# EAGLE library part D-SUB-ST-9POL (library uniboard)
D-SUB-Stecker, 9-polig, gewinkelt, RM 9,4

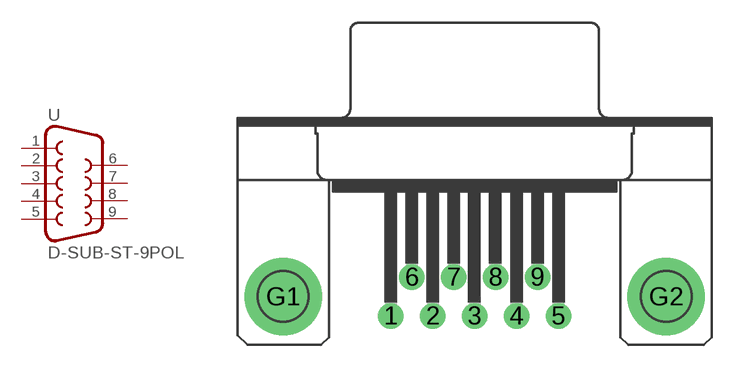
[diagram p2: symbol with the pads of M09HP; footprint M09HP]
Designator prefix -

## D-SUB-ST-9POL  [M09HP]
1  1  pas
2  2  pas
3  3  pas
4  4  pas
5  5  pas
6  6  pas
7  7  pas
8  8  pas
9  9  pas

## Footprint M09HP (pad centres in mm)
D-SUB-Stecker, 9-polig, gewinkelt
drill 1.016 pad 1.676 round: 1 -5.486,-1.27; 2 -2.743,-1.27; 3 0,-1.27; 4 2.743,-1.27; 5 5.486,-1.27; 6 -4.115,1.27; 7 -1.372,1.27; 8 1.372,1.27; 9 4.115,1.27
drill 3.302 pad 5.08 round: G1 -12.522,0; G2 12.522,0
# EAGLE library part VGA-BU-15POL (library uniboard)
VGA-Buchse 15pol

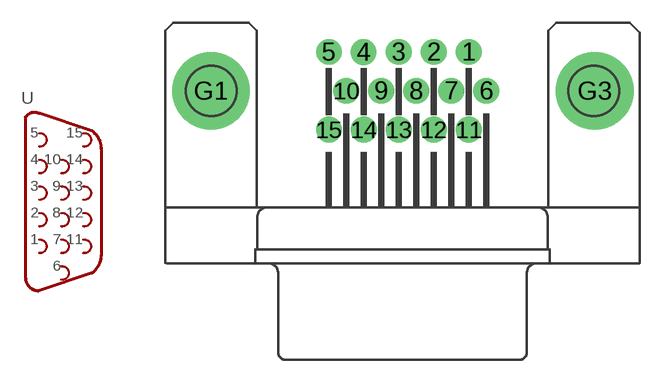
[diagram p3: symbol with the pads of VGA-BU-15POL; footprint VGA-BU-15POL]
Designator prefix -

## VGA-BU-15POL  [VGA-BU-15POL]
1  1  pas
2  2  pas
3  3  pas
4  4  pas
5  5  pas
6  6  pas
7  7  pas
8  8  pas
9  9  pas
10  10  pas
11  11  pas
12  12  pas
13  13  pas
14  14  pas
15  15  pas

## Footprint VGA-BU-15POL (pad centres in mm)
VGA-Buchse 15-polig
drill 1.016 pad 1.676 round: 1 4.329,2.54; 2 2.043,2.54; 3 -0.243,2.54; 4 -2.54,2.529; 5 -4.815,2.54; 6 5.472,0; 7 3.186,0; 8 0.9,0; 9 -1.386,0; 10 -3.672,0; 11 4.329,-2.54; 12 2.043,-2.54; 13 -0.243,-2.54; 14 -2.529,-2.54; 15 -4.815,-2.54
drill 3.302 pad 5.08 round: G1 -12.522,0; G3 12.56,0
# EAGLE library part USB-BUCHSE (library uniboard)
USB-Buchse Typ B

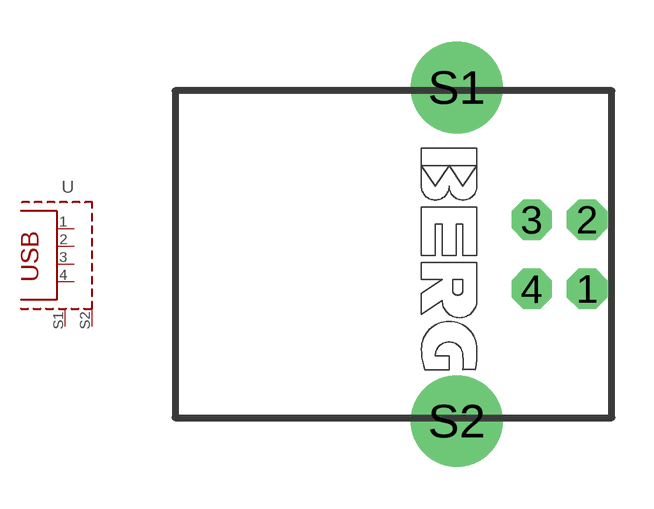
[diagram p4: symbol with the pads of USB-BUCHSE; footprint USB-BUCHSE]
Designator prefix -

## USB-BUCHSE  [USB-BUCHSE]
1  1  pas
2  2  pas
3  3  pas
4  4  pas
S1  5  pas
S2  6  pas

## Footprint USB-BUCHSE (pad centres in mm)
USB-Buchse Typ B
drill 0.95 octagon: 1 7.25,-1.25; 2 7.25,1.25; 3 5.25,1.25; 4 5.25,-1.25
drill 2.3 pad 2.9 round: S1 2.54,6.02; S2 2.54,-6.02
